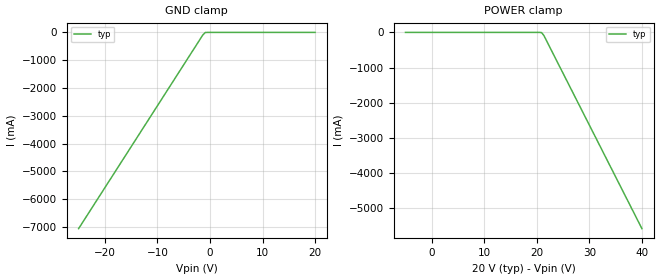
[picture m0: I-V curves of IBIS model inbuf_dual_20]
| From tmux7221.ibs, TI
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| inbuf_dual_20
[Model]   inbuf_dual_20
Model_type   Input
Vinl = 0.8
Vinh = 1.3
|   typ   min   max
C_comp   4.014581e-13   NA   NA
[Voltage Range]   20   NA   NA
[Temperature Range]   27   NA   NA
[Power Clamp Reference]   20   NA   NA
[GND Clamp Reference]   0   NA   NA
[GND Clamp]
|   Voltage   I(typ)   I(min)   I(max)
-25V      -7.06A     NA         NA
-1.364V   -94.53mA   NA         NA
-909.1mV  -5.152mA   NA         NA
-454.5mV  -3.845uA   NA         NA
20V       1.074uA    NA         NA
[POWER Clamp]
|   Voltage   I(typ)   I(min)   I(max)
-5V       1.316uA    NA         NA
20.45V    -3.845uA   NA         NA
20.91V    -5.152mA   NA         NA
21.36V    -94.53mA   NA         NA
40V       -5.586A    NA         NA
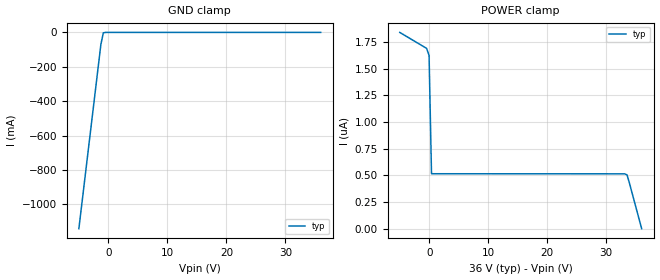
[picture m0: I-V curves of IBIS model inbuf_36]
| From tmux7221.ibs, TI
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| inbuf_36
[Model]   inbuf_36
Model_type   Input
Vinl = 0.8
Vinh = 1.3
|   typ   min   max
C_comp   4.014581e-13   NA   NA
[Voltage Range]   36   NA   NA
[Temperature Range]   27   NA   NA
[Power Clamp Reference]   36   NA   NA
[GND Clamp Reference]   0   NA   NA
[GND Clamp]
|   Voltage   I(typ)   I(min)   I(max)
-5V       -1.141A    NA         NA
-1.273V   -71.03mA   NA         NA
-858.6mV  -2.424mA   NA         NA
-444.4mV  -3.234uA   NA         NA
36V       1.541uA    NA         NA
[POWER Clamp]
|   Voltage   I(typ)   I(min)   I(max)
-5V       1.841uA    NA         NA
-444.4mV  1.691uA    NA         NA
-30.3mV   1.624uA    NA         NA
383.8mV   515nA      NA         NA
33.1V     514.2nA    NA         NA
33.52V    504.8nA    NA         NA
33.93V    426.7nA    NA         NA
36V       -194.6pA   NA         NA
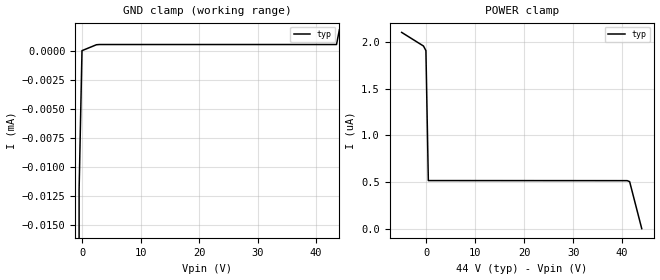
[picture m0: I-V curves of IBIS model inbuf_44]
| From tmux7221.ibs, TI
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| inbuf_44
[Model]   inbuf_44
Model_type   Input
Vinl = 0.8
Vinh = 1.3
|   typ   min   max
C_comp   2.533030e-13   NA   NA
[Voltage Range]   44   NA   NA
[Temperature Range]   27   NA   NA
[Power Clamp Reference]   44   NA   NA
[GND Clamp Reference]   0   NA   NA
[GND Clamp]
|   Voltage   I(typ)   I(min)   I(max)
-5V       -1.141A    NA         NA
-1.04V    -19.29mA   NA         NA
-545.5mV  -11.93uA   NA         NA
-50.51mV  -10.66nA   NA         NA
2.424V    496.1nA    NA         NA
2.919V    514.2nA    NA         NA
43.51V    515.1nA    NA         NA
44V       1.777uA    NA         NA
[POWER Clamp]
|   Voltage   I(typ)   I(min)   I(max)
-5V       2.103uA    NA         NA
-545.5mV  1.957uA    NA         NA
-50.5mV   1.908uA    NA         NA
444.4mV   515.1nA    NA         NA
41.03V    514.3nA    NA         NA
41.53V    503.5nA    NA         NA
44V       -234.8pA   NA         NA
